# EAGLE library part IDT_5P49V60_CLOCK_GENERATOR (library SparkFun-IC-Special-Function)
Clock Generator 5P49V60 The 5P49V60 is a programmable clock generator intended for automotive applications. Configurations may be stored in on-chip One-Time Programmable (OTP) memory or changed using I2C interface. This is IDT’s sixth generation of programmable clock technology (VersaClock 6E). The frequencies are generated from a single reference clock. The reference clock can come from one of the two redundant clock inputs. A glitchless manual switchover function allows one of the redundant clocks to be selected during normal operation. Two select pins allow up to four different configurations to be programmed and accessible using processor GPIOs or bootstrapping. The different selections may be used for different operating modes (full function, partial function, partial power-down), regional standards (US, Japan, Europe) or system production margin testing. The device may be configured to use one of two I2C addresses to allow multiple devices to be used in a system.

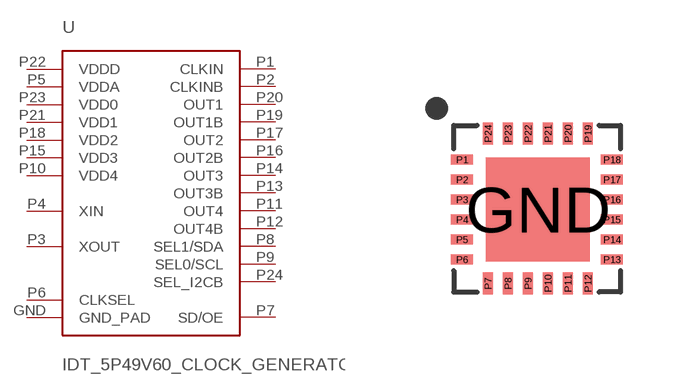
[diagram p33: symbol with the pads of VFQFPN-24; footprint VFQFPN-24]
Designator prefix U

## IDT_5P49V60_CLOCK_GENERATOR (PROD_ID: IC-14612)  [VFQFPN-24]
GND  GND_PAD  pwr
P1  CLKIN
P2  CLKINB  pwr
P3  XOUT
P4  XIN
P5  VDDA  pwr
P6  CLKSEL  pwr
P7  SD/OE
P8  SEL1/SDA
P9  SEL0/SCL
P10  VDD4  pwr
P11  OUT4
P12  OUT4B
P13  OUT3B
P14  OUT3
P15  VDD3  pwr
P16  OUT2B
P17  OUT2
P18  VDD2  pwr
P19  OUT1B
P20  OUT1
P21  VDD1  pwr
P22  VDDD  pwr
P23  VDD0  pwr
P24  SEL_I2CB  pwr

## Footprint VFQFPN-24 (pad centres in mm)
24-VFQFPN Specifications: Pin count: 24 Pin pitch: .5mm Pin size: .55mm x .25mm Total Size: 4.3mm x 4.3mm
smd 2.6 x 2.6: GND 0,0
smd 0.55 x 0.25: P1 -1.9,1.25; P2 -1.9,0.75; P3 -1.9,0.25; P4 -1.9,-0.25; P5 -1.9,-0.75; P6 -1.9,-1.25; P13 1.85,-1.25; P14 1.85,-0.75; P15 1.85,-0.25; P16 1.85,0.25; P17 1.85,0.75; P18 1.85,1.25
smd 0.25 x 0.55: P7 -1.25,-1.85; P8 -0.75,-1.85; P9 -0.25,-1.85; P10 0.25,-1.85; P11 0.75,-1.85; P12 1.25,-1.85; P19 1.25,1.9; P20 0.75,1.9; P21 0.25,1.9; P22 -0.25,1.9; P23 -0.75,1.9; P24 -1.25,1.9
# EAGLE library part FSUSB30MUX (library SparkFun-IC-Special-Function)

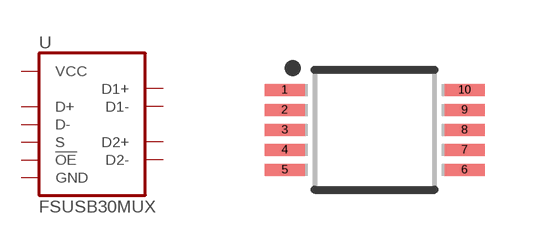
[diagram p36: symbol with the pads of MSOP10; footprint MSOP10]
Designator prefix U

## FSUSB30MUX_MSOP10 (PROD_ID: IC-15569)  [MSOP10]
1  S
2  D1+
3  D2+
4  D+
5  GND
6  D-
7  D2-
8  D1-
9  !OE!
10  VCC

## Footprint MSOP10 (pad centres in mm)
MSOP10 Mechanical Specifications: Pad Size:1.4mm x .3mm Pin count: 10 Pin pitch: .5mm Package Size: 3mm x 3mm Datasheet referenced for footprint
smd 1 x 0.3: 1 -2.25,1; 2 -2.25,0.5; 3 -2.25,0; 4 -2.25,-0.5; 5 -2.25,-1; 6 2.25,-1; 7 2.25,-0.5; 8 2.25,0; 9 2.25,0.5; 10 2.25,1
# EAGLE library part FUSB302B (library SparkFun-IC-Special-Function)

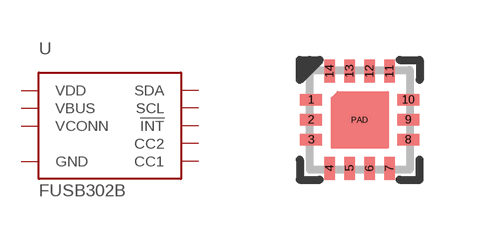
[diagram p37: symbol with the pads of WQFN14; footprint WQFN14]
Designator prefix U

## FUSB302B-MPX  [WQFN14]
1  CC2
2  VBUS
3  VDD
4  VDD
5  !INT
6  SCL
7  SDA
8  GND
9  GND
10  CC1
11  CC1
12  VCONN
13  VCONN
14  CC2
PAD  GND

## Footprint WQFN14 (pad centres in mm)
smd 0.58 x 0.3: 1 -1.215,0.5; 2 -1.215,0; 3 -1.215,-0.5; 8 1.215,-0.5; 9 1.215,0; 10 1.215,0.5
smd 0.3 x 0.58: 4 -0.75,-1.215; 5 -0.25,-1.215; 6 0.25,-1.215; 7 0.75,-1.215; 11 0.75,1.215; 12 0.25,1.215; 13 -0.25,1.215; 14 -0.75,1.215
smd 0.25 x 0.25: PAD 0,0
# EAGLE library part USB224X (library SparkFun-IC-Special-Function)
Microchip Technology USB224x Flash Media Controller 36-QFN Source: Datasheet

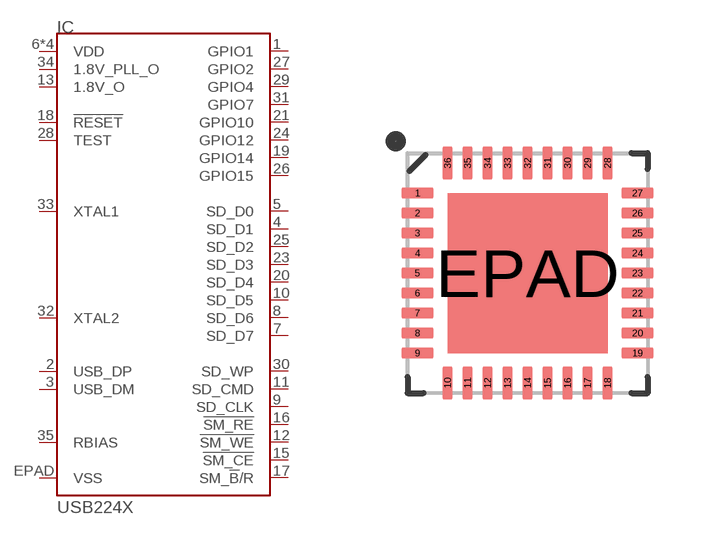
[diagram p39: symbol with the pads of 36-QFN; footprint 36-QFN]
Designator prefix IC

## USB224X_2241_V04 (PROD_ID: IC-16527)  [36-QFN]
1  GPIO1
2  USB_DP
3  USB_DM
4  SD_D1
5  SD_D0
6  VDD  pwr
7  SD_D7
8  SD_D6
9  SD_CLK
10  SD_D5
11  SD_CMD
12  !SM_WE!
13  1.8V_O  out
14  VDD  pwr
15  !SM_CE!
16  !SM_RE!
17  SM_!B!/R
18  !RESET!  in
19  GPIO14
20  SD_D4
21  GPIO10
22  VDD  pwr
23  SD_D3
24  GPIO12
25  SD_D2
26  GPIO15
27  GPIO2
28  TEST
29  GPIO4
30  SD_WP
31  GPIO7
32  XTAL2
33  XTAL1
34  1.8V_PLL_O  out
35  RBIAS
36  VDD  pwr
EPAD  VSS  pwr

## Footprint 36-QFN (pad centres in mm)
36-QFN
smd 0.8 x 0.25: 1 -2.75,2; 2 -2.75,1.5; 3 -2.75,1; 4 -2.75,0.5; 5 -2.75,0; 6 -2.75,-0.5; 7 -2.75,-1; 8 -2.75,-1.5; 9 -2.75,-2; 19 2.75,-2; 20 2.75,-1.5; 21 2.75,-1; 22 2.75,-0.5; 23 2.75,0; 24 2.75,0.5; 25 2.75,1; 26 2.75,1.5; 27 2.75,2
smd 0.25 x 0.8: 10 -2,-2.75; 11 -1.5,-2.75; 12 -1,-2.75; 13 -0.5,-2.75; 14 0,-2.75; 15 0.5,-2.75; 16 1,-2.75; 17 1.5,-2.75; 18 2,-2.75; 28 2,2.75; 29 1.5,2.75; 30 1,2.75; 31 0.5,2.75; 32 0,2.75; 33 -0.5,2.75; 34 -1,2.75; 35 -1.5,2.75; 36 -2,2.75
smd 4 x 4: EPAD 0,0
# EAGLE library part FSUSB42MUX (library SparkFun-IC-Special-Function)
Fairchild FSUSB42MUX he FSUSB42 is a bi-directional, low-power, two-port, high-speed, USB2.0 switch. Configured as a double- pole, double-throw switch (DPDT) switch, it is optimized for switching between any combination of high-speed (480 Mbps) or Full-Speed (12 Mbps) sources.

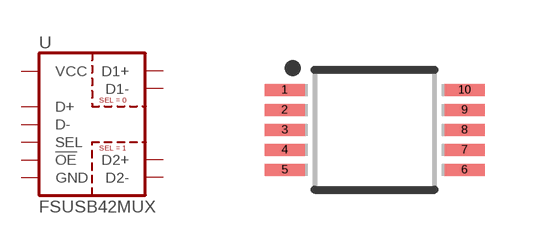
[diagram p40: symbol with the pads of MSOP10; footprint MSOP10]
Designator prefix U

## FSUSB42MUX (PROD_ID: IC-18702)  [MSOP10]
1  VCC
2  SEL
3  D+
4  D-
5  GND
6  D1-
7  D1+
8  D2-
9  D2+
10  !OE!

## Footprint MSOP10 (pad centres in mm)
MSOP10 Mechanical Specifications: Pad Size:1.4mm x .3mm Pin count: 10 Pin pitch: .5mm Package Size: 3mm x 3mm Datasheet referenced for footprint
smd 1 x 0.3: 1 -2.25,1; 2 -2.25,0.5; 3 -2.25,0; 4 -2.25,-0.5; 5 -2.25,-1; 6 2.25,-1; 7 2.25,-0.5; 8 2.25,0; 9 2.25,0.5; 10 2.25,1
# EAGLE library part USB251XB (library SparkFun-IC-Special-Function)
USB 2.0 Hi-Speed Hub Controller USB2514B is four-port

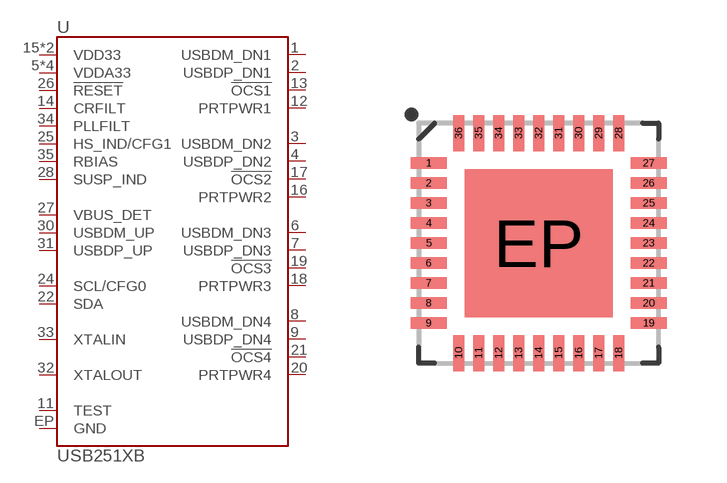
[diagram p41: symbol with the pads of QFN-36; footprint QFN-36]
Designator prefix U

## USB251XB_USB2514B (PROD_ID: IC-15827)  [QFN-36]
1  USBDM_DN1
2  USBDP_DN1
3  USBDM_DN2
4  USBDP_DN2
5  VDDA33
6  USBDM_DN3
7  USBDP_DN3
8  USBDM_DN4
9  USBDP_DN4
10  VDDA33
11  TEST
12  PRTPWR1
13  !OCS1
14  CRFILT
15  VDD33
16  PRTPWR2
17  !OCS2
18  PRTPWR3
19  !OCS3
20  PRTPWR4
21  !OCS4
22  SDA
23  VDD33
24  SCL/CFG0
25  HS_IND/CFG1
26  !RESET
27  VBUS_DET
28  SUSP_IND
29  VDDA33
30  USBDM_UP
31  USBDP_UP
32  XTALOUT
33  XTALIN
34  PLLFILT
35  RBIAS
36  VDDA33
EP  GND

## Footprint QFN-36 (pad centres in mm)
smd 0.9 x 0.28: 1 -2.75,2; 2 -2.75,1.5; 3 -2.75,1; 4 -2.75,0.5; 5 -2.75,0; 6 -2.75,-0.5; 7 -2.75,-1; 8 -2.75,-1.5; 9 -2.75,-2; 19 2.75,-2; 20 2.75,-1.5; 21 2.75,-1; 22 2.75,-0.5; 23 2.75,0; 24 2.75,0.5; 25 2.75,1; 26 2.75,1.5; 27 2.75,2
smd 0.28 x 0.9: 10 -2,-2.75; 11 -1.5,-2.75; 12 -1,-2.75; 13 -0.5,-2.75; 14 0,-2.75; 15 0.5,-2.75; 16 1,-2.75; 17 1.5,-2.75; 18 2,-2.75; 28 2,2.75; 29 1.5,2.75; 30 1,2.75; 31 0.5,2.75; 32 0,2.75; 33 -0.5,2.75; 34 -1,2.75; 35 -1.5,2.75; 36 -2,2.75
smd 3.7 x 3.7: EP 0,0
